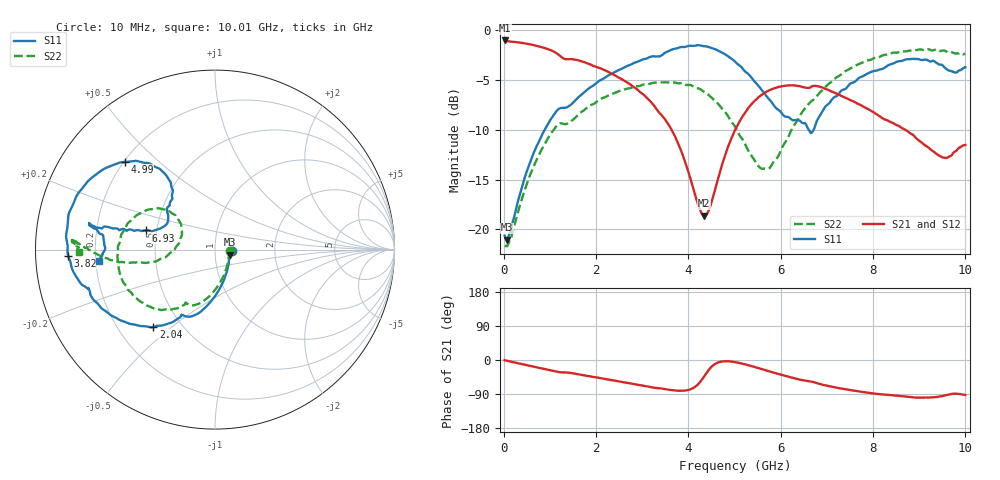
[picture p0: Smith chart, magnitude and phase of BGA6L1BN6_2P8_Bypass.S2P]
!Agilent Technologies,E5071C,MY46317100,A.11.08
!Date: Wed Jun 03 12:58:54 2015
!Data & Calibration Information:
!Freq	S11:SOLT2(ON)	S21:SOLT2(ON)	S12:SOLT2(ON)	S22:SOLT2(ON)
!PortZ  Port1:50+j0  Port2:50+j0
!Above PortZ is port z conversion or system Z0 setting when saving the data.
!When reading, reference impedance value at option line is always used.
# Hz S RI R 50
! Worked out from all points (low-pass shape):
!   1001 points, 10 MHz to 10.01 GHz, reference 50 ohm
!   highest |S21| = -1.05 dB at 10 MHz (marker M1); lowest = -18.6 dB at 4.34 GHz (marker M2)
!   |S21| within 3 dB of the highest: start of sweep to 2.186 GHz
!   lowest |S11| = -21.0 dB at 60 MHz (marker M3), VSWR 1.19, Z = 59.1 - j3.46 ohm
!   |S11| at or under -10 dB: start of sweep to 882.7 MHz; 6.611 GHz to 6.717 GHz (106.6 MHz wide, 1.6 % of centre)
!   |S22| runs from -21.7 to -1.9 dB; largest |S21 - S12| = 0.0079
!   S11 on the Smith chart (normalised r, x): 10 MHz: 1.20, -0.02; 2.04 GHz: 0.35, -0.43; 3.82 GHz: 0.10, -0.02; 4.99 GHz: 0.20, +0.39; 6.93 GHz: 0.44, +0.11; 10.01 GHz: 0.21, -0.05
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1e7  0.0926 -0.00841  0.8856 -0.00826  0.8806 -0.00588  0.0825 -0.0053
6e7  0.0839 -0.0291  0.8777 -0.0315  0.8761 -0.0292  0.0792 -0.0228
5e8  0.0378 -0.1943  0.8269 -0.2053  0.8274 -0.2038  0.0374 -0.1668
8.5e8  -0.0362 -0.3043  0.7501 -0.3199  0.7507 -0.3185  -0.0305 -0.2592
1.16e9  -0.1366 -0.3734  0.6476 -0.3926  0.6485 -0.3911  -0.1232 -0.3106
1.68e9  -0.2443 -0.4072  0.5392 -0.4409  0.5405 -0.4392  -0.2099 -0.3271
2.04e9  -0.3431 -0.4315  0.4434 -0.4718  0.4446 -0.4704  -0.2904 -0.3357
2.7e9  -0.5372 -0.3885  0.264 -0.4712  0.2651 -0.4692  -0.4232 -0.2838
3.35e9  -0.7051 -0.214  0.1025 -0.3744  0.1057 -0.3726  -0.5265 -0.1451
3.82e9  -0.819 -0.0333  0.0386 -0.2518  0.0405 -0.2512  -0.5405 0.00615
4.34e9  -0.7831 0.2713  0.0854 -0.0801  0.086 -0.0794  -0.4559 0.1723
4.71e9  -0.6398 0.4357  0.2036 -0.0155  0.2036 -0.0136  -0.3388 0.2271
4.99e9  -0.5034 0.4879  0.3059 -0.0274  0.3063 -0.0241  -0.2556 0.2148
5.01e9  -0.4919 0.4888  0.3129 -0.0305  0.3131 -0.0272  -0.2514 0.2113
5.51e9  -0.2954 0.4381  0.4269 -0.1647  0.4281 -0.1599  -0.184 0.0993
5.73e9  -0.2495 0.3799  0.4326 -0.2403  0.4347 -0.2352  -0.1971 0.0411
6.68e9  -0.2743 0.1363  0.2835 -0.4376  0.2882 -0.4317  -0.436 -0.0703
6.93e9  -0.384 0.1066  0.2094 -0.4662  0.2148 -0.4626  -0.4989 -0.0732
8.35e9  -0.6567 0.1219  -0.0128 -0.3485  -0.00716 -0.348  -0.7556 0.0308
8.87e9  -0.7003 0.1453  -0.0433 -0.2955  -0.0386 -0.2942  -0.7885 0.0423
9.47e9  -0.6602 0.1184  -0.0239 -0.2313  -0.018 -0.2318  -0.7828 0.04
1.001e10  -0.6476 -0.0614  -0.0104 -0.2648  -0.00597 -0.2658  -0.759 -0.0122
